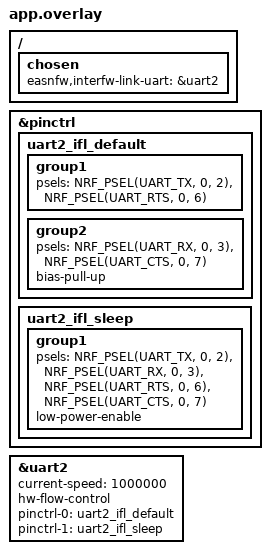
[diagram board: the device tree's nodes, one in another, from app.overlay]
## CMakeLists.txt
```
cmake_minimum_required(VERSION 3.20.0)

find_package(Zephyr)
project(EASN_FW)

target_include_directories(app PRIVATE include ../../shared)

target_sources(app PRIVATE
	src/main.c
	src/application/sensor_link.c
	src/application/payload_assembler.c
	src/application/cloud_tx.c
	src/domain/payload_format.c
	src/domain/selftest.c
	src/platform/http_client.c
	src/platform/lte_m.c
	src/platform/uart.c
	src/shared/retry.c
)
```

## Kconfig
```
mainmenu "EASNFW-CLOUD"

menu "EASNFW-CLOUD image"

choice EASNFW_IMAGE_TYPE
	prompt "Image type"
	default EASNFW_IMAGE_TYPE_DEVELOPMENT

config EASNFW_IMAGE_TYPE_PRODUCTION
	bool "Production image"

config EASNFW_IMAGE_TYPE_DEVELOPMENT
	bool "Development image"

config EASNFW_IMAGE_TYPE_DEBUG
	bool "Debug image"

config EASNFW_IMAGE_TYPE_HIL
	bool "HIL verification image"
	select SHELL
	select SHELL_BACKEND_SERIAL
	select REBOOT

endchoice

config EASNFW_VERIFICATION_CODE
	def_bool EASNFW_IMAGE_TYPE_HIL

endmenu

menuconfig EASNFW_IFL_UART
	bool "EASNFW UART link"
	default y
	depends on SERIAL && UART_ASYNC_API && RING_BUFFER
	depends on UART_2_ASYNC && UART_USE_RUNTIME_CONFIGURE

if EASNFW_IFL_UART
config EASNFW_IFL_UART_RX_RING_BUF_SIZE
	int "RX buffer size"
	default 2048
endif

config EASNFW_CLOUD_MAX_RECORD_SIZE
	int "Maximum in-memory record transfer size"
	range 1 65536
	default 16384
	help
	  Bounds the single record buffer used while receiving and forwarding one
	  sensor transfer. This is a volatile staging limit, not persistent storage.

source "Kconfig.zephyr"
```

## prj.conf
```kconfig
CONFIG_LOG=y
CONFIG_LOG_DEFAULT_LEVEL=3
CONFIG_LOG_BACKEND_UART=y
CONFIG_LOG_MODE_DEFERRED=y
CONFIG_MAIN_STACK_SIZE=1024
CONFIG_EASNFW_IFL_UART=y
CONFIG_SERIAL=y
CONFIG_UART_ASYNC_API=y
CONFIG_UART_2_ASYNC=y
CONFIG_UART_USE_RUNTIME_CONFIGURE=y
CONFIG_RING_BUFFER=y
CONFIG_REBOOT=y
CONFIG_ENTROPY_GENERATOR=y
CONFIG_HWINFO=y
CONFIG_FLASH=y
CONFIG_FLASH_MAP=y
CONFIG_STREAM_FLASH=y
CONFIG_IMG_MANAGER=y
CONFIG_MCUBOOT_IMG_MANAGER=y
CONFIG_NRF_MODEM_LIB=y
CONFIG_LTE_LINK_CONTROL=y
CONFIG_DATE_TIME=y
CONFIG_DATE_TIME_MODEM=y
CONFIG_DATE_TIME_AUTO_UPDATE=y
CONFIG_DATE_TIME_NTP=n
```

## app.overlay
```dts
&pinctrl {
	uart2_ifl_default: uart2_ifl_default {
		group1 {
			psels = <NRF_PSEL(UART_TX, 0, 2)>,
				<NRF_PSEL(UART_RTS, 0, 6)>;
		};
		group2 {
			psels = <NRF_PSEL(UART_RX, 0, 3)>,
				<NRF_PSEL(UART_CTS, 0, 7)>;
			bias-pull-up;
		};
	};

	uart2_ifl_sleep: uart2_ifl_sleep {
		group1 {
			psels = <NRF_PSEL(UART_TX, 0, 2)>,
				<NRF_PSEL(UART_RX, 0, 3)>,
				<NRF_PSEL(UART_RTS, 0, 6)>,
				<NRF_PSEL(UART_CTS, 0, 7)>;
			low-power-enable;
		};
	};
};

&uart2 {
	status = "okay";
	current-speed = <1000000>;
	hw-flow-control;
	pinctrl-0 = <&uart2_ifl_default>;
	pinctrl-1 = <&uart2_ifl_sleep>;
	pinctrl-names = "default", "sleep";
};

/ {
	chosen {
		easnfw,interfw-link-uart = &uart2;
	};
};
```

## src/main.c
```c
#include <errno.h>
#include <zephyr/kernel.h>
#include <zephyr/logging/log.h>
#ifdef CONFIG_BOOTLOADER_MCUBOOT
#include <zephyr/dfu/mcuboot.h>
#endif
#include <easnfw/pipeline.h>
#include <easnfw/cloud_tx.h>
#include <easnfw/payload_assembler.h>
#include <easnfw/sensor_link.h>
#include <easnfw/selftest.h>

LOG_MODULE_REGISTER(easnfw_cloud, LOG_LEVEL_INF);

K_MSGQ_DEFINE(rx_payload_q, sizeof(struct easnfw_pipeline_message), 1, 4);
K_MSGQ_DEFINE(assembled_payload_q, sizeof(struct easnfw_pipeline_message), 1, 4);
K_MSGQ_DEFINE(tx_result_q, sizeof(struct easnfw_pipeline_message), 1, 4);
K_MEM_SLAB_DEFINE(easnfw_record_pool, CONFIG_EASNFW_CLOUD_MAX_RECORD_SIZE, 1, 4);

/**
 * @brief Allocate bounded volatile staging memory for one incoming record.
 *
 * @param data Receives the allocated buffer address.
 * @return 0 on success or a negative errno value.
 */
int easnfw_record_buffer_alloc(uint8_t **data)
{
	if (data == NULL) {
		return -EINVAL;
	}
	return k_mem_slab_alloc(&easnfw_record_pool, (void **)data, K_NO_WAIT);
}

/**
 * @brief Release the cloud's single record staging buffer.
 *
 * @param data Buffer previously returned by easnfw_record_buffer_alloc().
 */
void easnfw_record_buffer_free(uint8_t *data)
{
	if (data != NULL) {
		k_mem_slab_free(&easnfw_record_pool, data);
	}
}

int main(void)
{
	int err;

	LOG_INF("EASNFW-CLOUD starting");
	err = easnfw_cloud_ifl_init();
	if (err != 0) {
		LOG_ERR("Cloud IFL initialization failed");
		return -1;
	}

	if (easnfw_selftest_run() != 0) {
		LOG_ERR("Cloud self-test reports degraded mode; backend transport unavailable");
	}

#ifdef CONFIG_BOOTLOADER_MCUBOOT
	/* EASNFW_REVISIT: refine confirmation criteria with the cloud contract. */
	err = boot_write_img_confirmed();
	if (err != 0) {
		LOG_ERR("Could not confirm MCUboot image: %d", err);
	}
#endif
	sensor_link_start();
	payload_assembler_start();
	cloud_tx_start();
	LOG_INF("EASNFW-CLOUD ready (receive-only until backend contract is implemented)");
	return 0;
}
```
